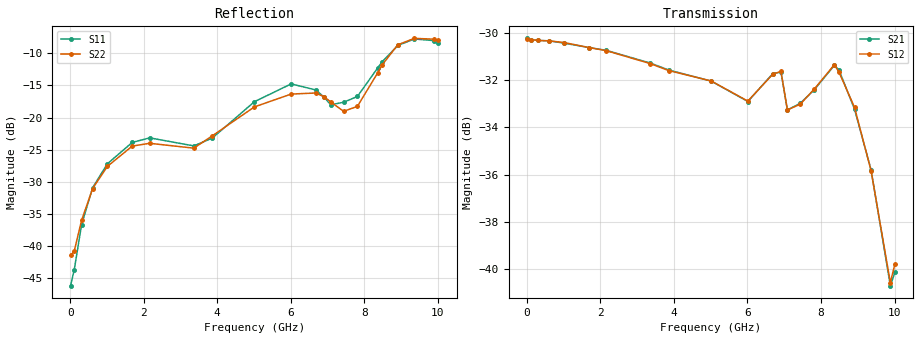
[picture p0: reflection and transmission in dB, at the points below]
! Device ID: PE43705
! Serial: 1
! Insertion: A
! Impedance: 50 ohm
! Temp: 25C
! VDD: 3.400V
! Attenuation Step: 29.25dB
#  Hz  S  RI  R  50
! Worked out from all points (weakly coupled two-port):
!   401 points, 10 MHz to 10.01 GHz, reference 50 ohm
!   highest |S21| = -30.24 dB at 10 MHz (marker M1); lowest = -40.7 dB at 9.885 GHz (marker M2)
!   lowest |S11| = -46.2 dB at 10 MHz (marker M3), VSWR 1.01, Z = 49.5 + j0.0447 ohm
!   |S11| at or under -10 dB: start of sweep to 8.673 GHz
!   |S22| runs from -41.6 to -7.5 dB; largest |S21 - S12| = 0.00066
!   S11 on the Smith chart (normalised r, x): 10 MHz: 0.99, +0.00; 7.435 GHz: 0.82, +0.16; 8.485 GHz: 0.84, +0.49; 9.36 GHz: 0.55, +0.49; 10.01 GHz: 0.49, +0.27
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1e7  -0.00486 0.000452  0.0308 -0.00012  0.0307 -0.000139  -0.00839 0.000488
1.1e8  -0.00451 0.00469  0.0306 -0.000835  0.0306 -0.000867  -0.00784 0.00461
3.1e8  -0.00687 0.0129  0.0304 -0.00231  0.0304 -0.00232  -0.0098 0.0124
6.1e8  -0.0159 0.0235  0.0301 -0.00449  0.0301 -0.00443  -0.0175 0.0218
1.01e9  -0.0337 0.0276  0.0292 -0.00725  0.0293 -0.00723  -0.0329 0.0254
1.685e9  -0.0614 0.0177  0.0272 -0.0113  0.0272 -0.0113  -0.0571 0.0178
2.16e9  -0.0693 0.00433  0.0254 -0.0141  0.0254 -0.014  -0.0625 0.00769
3.36e9  -0.0599 0.00489  0.0195 -0.0191  0.0195 -0.019  -0.0564 0.0122
3.86e9  -0.0631 0.0279  0.0171 -0.0201  0.0171 -0.02  -0.0666 0.027
5.01e9  -0.0992 0.0885  0.0126 -0.0216  0.0128 -0.0215  -0.1027 0.0641
6.01e9  -0.1512 0.103  0.00792 -0.0212  0.00806 -0.0212  -0.1303 0.0792
6.685e9  -0.1415 0.0828  0.00646 -0.0251  0.00615 -0.0251  -0.1372 0.0729
6.91e9  -0.1229 0.0743  0.00268 -0.026  0.00256 -0.0261  -0.1255 0.0724
7.085e9  -0.1077 0.065  0.00091 -0.0217  0.0009 -0.0217  -0.1079 0.0767
7.435e9  -0.0891 0.0967  0.00246 -0.0223  0.00246 -0.0222  -0.0736 0.0841
7.81e9  -0.0419 0.1399  0.00255 -0.0238  0.00239 -0.0239  -0.0477 0.1125
8.36e9  -0.0086 0.243  -0.00603 -0.0263  -0.00599 -0.0264  -0.0366 0.2195
8.485e9  -0.0149 0.2723  -0.00828 -0.0251  -0.00832 -0.0248  -0.0441 0.2538
8.91e9  -0.0712 0.3577  -0.012 -0.0182  -0.0122 -0.0183  -0.1069 0.3539
9.36e9  -0.1708 0.3727  -0.0108 -0.0121  -0.0106 -0.0122  -0.1995 0.3633
9.885e9  -0.2852 0.2779  -0.00294 -0.00873  -0.00304 -0.00884  -0.3252 0.2474
1.001e10  -0.3022 0.2363  -0.000955 -0.00979  -0.00098 -0.0102  -0.3473 0.1975
